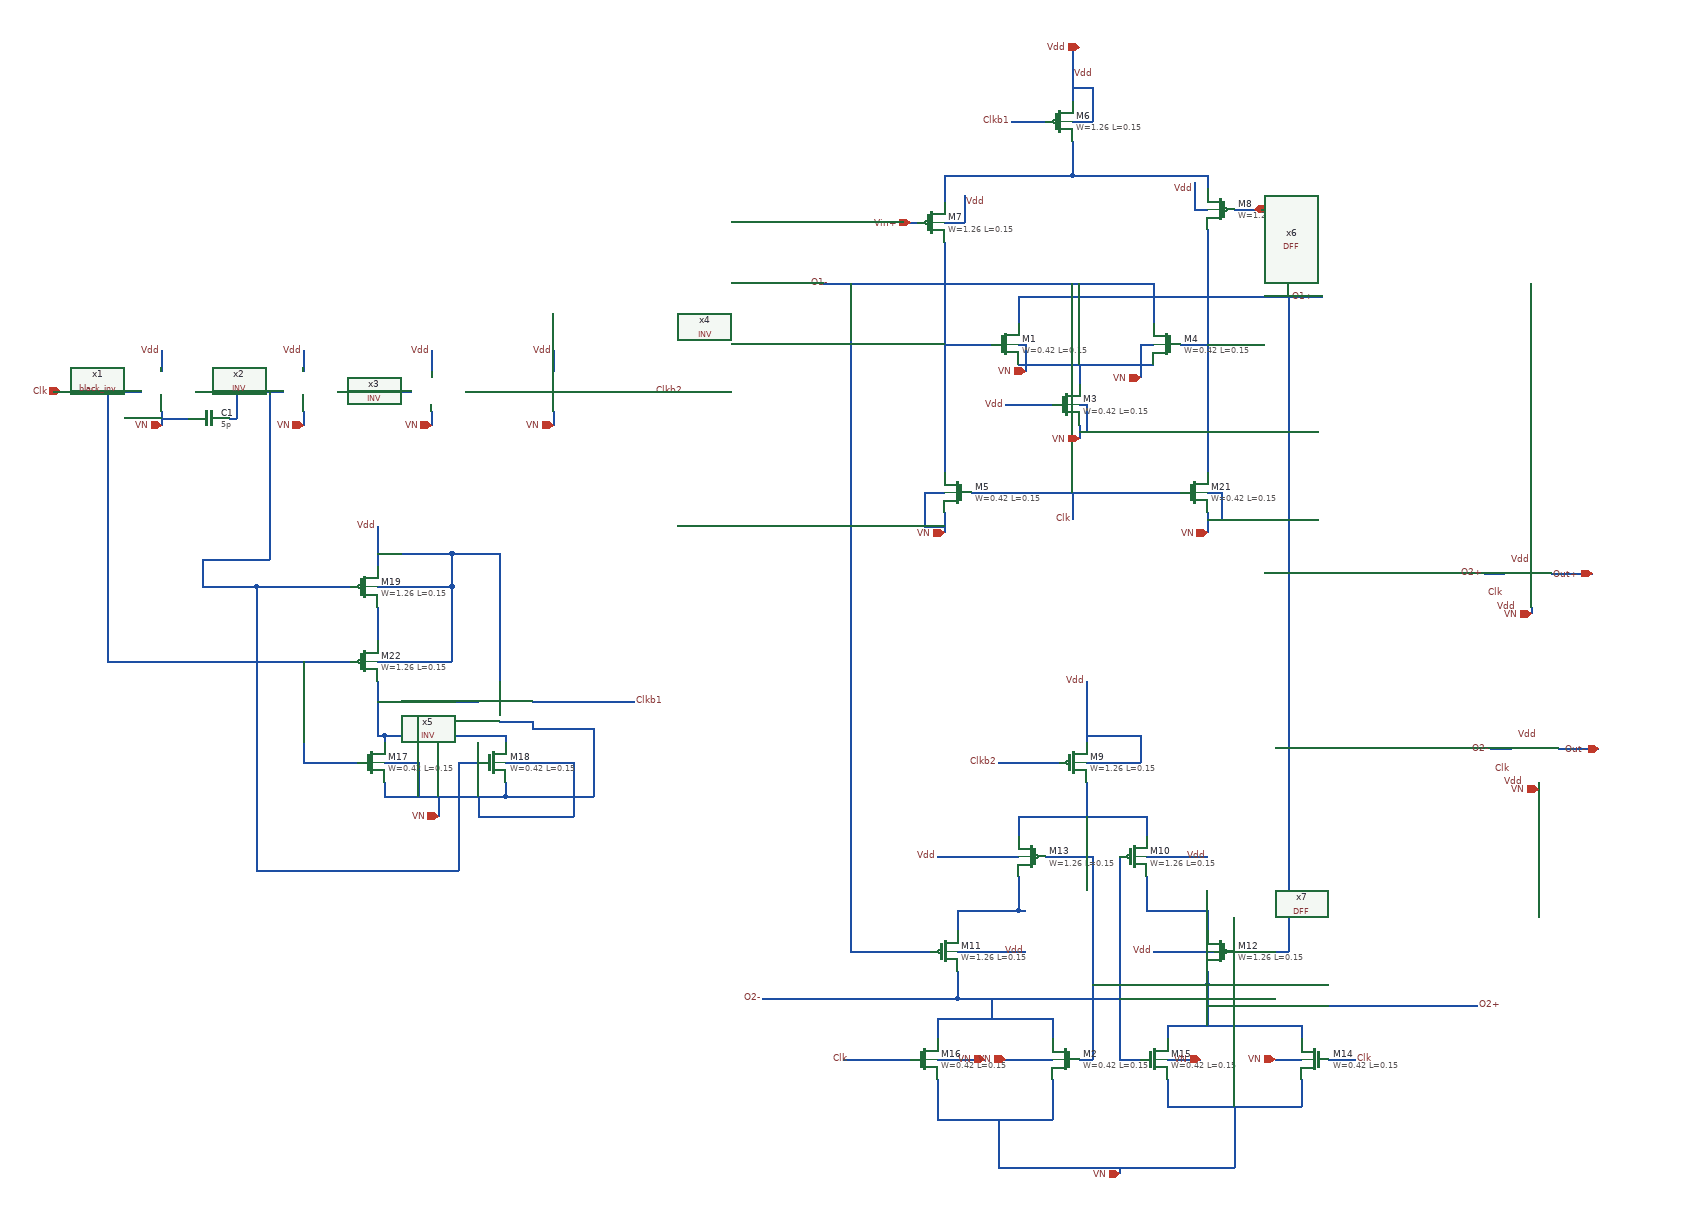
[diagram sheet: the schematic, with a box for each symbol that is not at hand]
v {xschem version=3.0.0 file_version=1.2 }
G {}
K {}
V {}
S {}
E {}
N 1790 -1710 1790 -1660 {
lab=#net1}
N 1790 -1660 1990 -1660 {
lab=#net1}
N 1990 -1660 1990 -1640 {
lab=#net1}
N 1600 -1660 1790 -1660 {
lab=#net1}
N 1600 -1660 1600 -1620 {
lab=#net1}
N 1990 -1580 1990 -1220 {
lab=O1+}
N 1600 -1560 1600 -1220 {
lab=O1-}
N 1640 -1190 1950 -1190 {
lab=Clk}
N 1710 -1380 1910 -1380 {
lab=#net2}
N 1800 -1380 1800 -1350 {
lab=#net2}
N 1690 -1320 1760 -1320 {
lab=Vdd}
N 1710 -1480 1710 -1440 {
lab=O1+}
N 1710 -1480 1990 -1480 {
lab=O1+}
N 1910 -1500 1910 -1440 {
lab=O1-}
N 1600 -1500 1910 -1500 {
lab=O1-}
N 1600 -1410 1670 -1410 {
lab=O1-}
N 1950 -1410 1990 -1410 {
lab=O1+}
N 1790 -1850 1790 -1770 {
lab=Vdd}
N 1700 -1740 1750 -1740 {
lab=Clkb1}
N 1600 -1160 1600 -1130 {
lab=VN}
N 1990 -1160 1990 -1130 {
lab=VN}
N 1800 -1290 1800 -1270 {
lab=VN}
N 1540 -1590 1560 -1590 {
lab=Vin+}
N 2030 -1610 2070 -1610 {
lab=Vin-}
N 1990 -1480 2160 -1480 {
lab=O1+}
N 1420 -1500 1600 -1500 {
lab=O1-}
N 1790 -1190 1790 -1150 {
lab=Clk}
N 1790 -1790 1820 -1790 {
lab=Vdd}
N 1820 -1790 1820 -1740 {
lab=Vdd}
N 1790 -1740 1820 -1740 {
lab=Vdd}
N 1630 -1630 1630 -1590 {
lab=Vdd}
N 1600 -1590 1630 -1590 {
lab=Vdd}
N 1970 -1650 1970 -1610 {
lab=Vdd}
N 1970 -1610 1990 -1610 {
lab=Vdd}
N 1710 -1410 1720 -1410 {
lab=VN}
N 1890 -1410 1910 -1410 {
lab=VN}
N 1800 -1280 1810 -1280 {
lab=VN}
N 1810 -1320 1810 -1280 {
lab=VN}
N 1800 -1320 1810 -1320 {
lab=VN}
N 1570 -1190 1600 -1190 {
lab=VN}
N 1570 -1190 1570 -1140 {
lab=VN}
N 1570 -1140 1600 -1140 {
lab=VN}
N 1990 -1190 2010 -1190 {
lab=VN}
N 2010 -1190 2010 -1150 {
lab=VN}
N 1990 -1150 2010 -1150 {
lab=VN}
N 1890 -1410 1890 -1360 {
lab=VN}
N 1810 -760 1810 -710 {
lab=#net3}
N 1710 -710 1710 -680 {
lab=#net3}
N 1900 -710 1900 -680 {
lab=#net3}
N 1710 -620 1710 -610 {
lab=#net4}
N 1710 -620 1710 -570 {
lab=#net4}
N 1620 -570 1710 -570 {
lab=#net4}
N 1620 -570 1620 -540 {
lab=#net4}
N 1990 -570 1990 -540 {
lab=#net5}
N 1900 -570 1990 -570 {
lab=#net5}
N 1900 -620 1900 -570 {
lab=#net5}
N 1860 -650 1860 -350 {
lab=O2-}
N 1860 -350 1890 -350 {
lab=O2-}
N 1800 -350 1820 -350 {
lab=O2+}
N 1820 -650 1820 -350 {
lab=O2+}
N 1750 -650 1820 -650 {
lab=O2+}
N 1990 -480 1990 -460 {
lab=O2+}
N 1820 -460 1990 -460 {
lab=O2+}
N 1620 -480 1620 -440 {
lab=O2-}
N 1620 -440 1860 -440 {
lab=O2-}
N 1760 -410 1760 -380 {
lab=O2-}
N 1590 -410 1760 -410 {
lab=O2-}
N 1590 -410 1590 -380 {
lab=O2-}
N 2130 -400 2130 -380 {
lab=O2+}
N 1930 -400 2130 -400 {
lab=O2+}
N 1930 -400 1930 -380 {
lab=O2+}
N 2130 -320 2130 -280 {
lab=VN}
N 1930 -280 2130 -280 {
lab=VN}
N 1930 -320 1930 -280 {
lab=VN}
N 1760 -320 1760 -260 {
lab=VN}
N 1590 -320 1590 -260 {
lab=VN}
N 1690 -350 1760 -350 {
lab=VN}
N 1590 -350 1660 -350 {
lab=VN}
N 2030 -280 2030 -190 {
lab=VN}
N 1680 -190 2030 -190 {
lab=VN}
N 1680 -260 1680 -190 {
lab=VN}
N 2030 -510 2110 -510 {
lab=O1+}
N 1540 -510 1580 -510 {
lab=O1-}
N 2170 -350 2210 -350 {
lab=Clk}
N 1450 -350 1550 -350 {
lab=Clk}
N 1900 -650 1990 -650 {
lab=Vdd}
N 1590 -650 1710 -650 {
lab=Vdd}
N 1990 -460 1990 -400 {
lab=O2+}
N 1670 -440 1670 -410 {
lab=O2-}
N 1620 -510 1720 -510 {
lab=Vdd}
N 1710 -570 1720 -570 {
lab=#net4}
N 1910 -510 2000 -510 {
lab=Vdd}
N 1930 -350 1980 -350 {
lab=VN}
N 2090 -350 2130 -350 {
lab=GND}
N 1810 -790 1890 -790 {
lab=Vdd}
N 1890 -830 1890 -790 {
lab=Vdd}
N 1870 -830 1890 -830 {
lab=Vdd}
N 1810 -830 1870 -830 {
lab=Vdd}
N 1810 -830 1810 -820 {
lab=Vdd}
N 1810 -910 1810 -820 {
lab=Vdd}
N 1690 -790 1770 -790 {
lab=Clkb2}
N 1680 -790 1690 -790 {
lab=Clkb2}
N 1330 -440 1620 -440 {
lab=O2-}
N 1990 -430 2230 -430 {
lab=O2+}
N 1710 -710 1900 -710 {
lab=#net3}
N 1460 -1500 1460 -510 {
lab=O1-}
N 1460 -510 1540 -510 {
lab=O1-}
N 2110 -1480 2110 -740 {
lab=O1+}
N 2110 -740 2110 -510 {
lab=O1+}
N 1590 -260 1760 -260 {
lab=VN}
N 700 -1340 810 -1340 {
lab=#net6}
N 890 -1340 990 -1340 {
lab=#net7}
N 440 -1400 440 -1370 {
lab=Vdd}
N 650 -1400 650 -1370 {
lab=Vdd}
N 840 -1400 840 -1370 {
lab=Vdd}
N 1020 -1400 1020 -1370 {
lab=Vdd}
N 280 -1340 410 -1340 {
lab=Clk}
N 360 -1340 360 -1140 {
lab=Clk}
N 1070 -1340 1170 -1340 {
lab=Clkb2}
N 440 -1310 440 -1290 {
lab=VN}
N 650 -1310 650 -1290 {
lab=VN}
N 840 -1310 840 -1290 {
lab=VN}
N 1020 -1310 1020 -1290 {
lab=VN}
N 360 -1140 360 -1110 {
lab=Clk}
N 760 -910 760 -830 {
lab=#net8}
N 760 -830 770 -830 {
lab=#net8}
N 770 -830 770 -820 {
lab=#net8}
N 770 -830 950 -830 {
lab=#net8}
N 950 -830 950 -820 {
lab=#net8}
N 760 -1020 760 -970 {
lab=#net9}
N 760 -1140 760 -1080 {
lab=Vdd}
N 770 -760 770 -740 {
lab=VN}
N 770 -740 950 -740 {
lab=VN}
N 950 -760 950 -740 {
lab=VN}
N 850 -740 850 -720 {
lab=VN}
N 630 -1050 720 -1050 {
lab=inv}
N 630 -940 720 -940 {
lab=Clk}
N 650 -790 730 -790 {
lab=Clk}
N 650 -940 650 -790 {
lab=Clk}
N 880 -790 910 -790 {
lab=inv}
N 880 -790 880 -710 {
lab=inv}
N 880 -710 880 -630 {
lab=inv}
N 580 -630 880 -630 {
lab=inv}
N 580 -1040 580 -630 {
lab=inv}
N 580 -1050 580 -1040 {
lab=inv}
N 580 -1050 630 -1050 {
lab=inv}
N 760 -1050 870 -1050 {
lab=Vdd}
N 760 -940 870 -940 {
lab=Vdd}
N 770 -790 820 -790 {
lab=VN}
N 950 -790 1050 -790 {
lab=VN}
N 820 -790 820 -740 {
lab=VN}
N 1050 -790 1050 -710 {
lab=VN}
N 910 -710 1050 -710 {
lab=VN}
N 910 -740 910 -710 {
lab=VN}
N 870 -1050 870 -940 {
lab=Vdd}
N 870 -1100 870 -1050 {
lab=Vdd}
N 760 -1100 870 -1100 {
lab=Vdd}
N 760 -880 910 -880 {
lab=#net8}
N 990 -880 1140 -880 {
lab=Clkb1}
N 940 -850 990 -850 {
lab=VN}
N 990 -850 990 -840 {
lab=VN}
N 870 -1100 940 -1100 {
lab=Vdd}
N 940 -1100 940 -940 {
lab=Vdd}
N 940 -940 940 -910 {
lab=Vdd}
N 950 -740 1080 -740 {
lab=VN}
N 1080 -840 1080 -740 {
lab=VN}
N 990 -840 1080 -840 {
lab=VN}
N 850 -720 850 -710 {
lab=VN}
N 360 -1110 360 -940 {
lab=Clk}
N 360 -940 630 -940 {
lab=Clk}
N 500 -1090 550 -1090 {
lab=inv}
N 500 -1090 500 -1050 {
lab=inv}
N 500 -1050 520 -1050 {
lab=inv}
N 520 -1050 580 -1050 {
lab=inv}
N 490 -1340 530 -1340 {
lab=inv}
N 590 -1340 620 -1340 {
lab=inv}
N 550 -1090 600 -1090 {
lab=inv}
N 600 -1340 600 -1090 {
lab=inv}
N 530 -1340 590 -1340 {
lab=inv}
N 440 -1300 480 -1300 {
lab=VN}
N 540 -1300 550 -1300 {
lab=inv}
N 550 -1340 550 -1300 {
lab=inv}
N 590 -1360 590 -1340 {
lab=inv}
N 2400 -1070 2430 -1070 {
lab=O2+}
N 2500 -1070 2560 -1070 {
lab=Out+}
N 2410 -810 2440 -810 {
lab=O2-}
N 2510 -810 2570 -810 {
lab=Out-}
N 2230 -430 2390 -430 {
lab=O2+}
N 2480 -760 2480 -750 {
lab=VN}
N 2470 -1020 2470 -1010 {
lab=VN}
N 1860 -190 1860 -180 {
lab=VN}
N 1720 -1410 1720 -1370 {
lab=VN}
C {devices/iopin.sym} 1550 -1590 0 0 {name=p2 lab=Vin+}
C {devices/iopin.sym} 2060 -1610 0 1 {name=p3 lab=Vin-}
C {devices/lab_pin.sym} 1690 -1320 0 0 {name=l5 sig_type=std_logic lab=Vdd}
C {devices/lab_pin.sym} 1970 -1640 0 0 {name=l18 sig_type=std_logic lab=Vdd}
C {devices/lab_pin.sym} 1630 -1620 2 0 {name=l19 sig_type=std_logic lab=Vdd}
C {devices/lab_pin.sym} 1810 -910 0 0 {name=l22 sig_type=std_logic lab=Vdd
}
C {devices/lab_pin.sym} 1590 -650 1 0 {name=l24 sig_type=std_logic lab=Vdd
}
C {devices/lab_pin.sym} 1990 -650 1 0 {name=l25 sig_type=std_logic lab=Vdd
}
C {devices/lab_pin.sym} 1720 -510 1 0 {name=l26 sig_type=std_logic lab=Vdd
}
C {devices/lab_pin.sym} 1910 -510 1 0 {name=l27 sig_type=std_logic lab=Vdd
}
C {sky130_fd_pr/pfet_01v8.sym} 1770 -1740 0 0 {name=M6
L=0.15
W=1.26
nf=1
mult=1
ad="'int((nf+1)/2) * W/nf * 0.29'" 
pd="'2*int((nf+1)/2) * (W/nf + 0.29)'"
as="'int((nf+2)/2) * W/nf * 0.29'" 
ps="'2*int((nf+2)/2) * (W/nf + 0.29)'"
nrd="'0.29 / W'" nrs="'0.29 / W'"
sa=0 sb=0 sd=0
model=pfet_01v8
spiceprefix=X
}
C {sky130_fd_pr/pfet_01v8.sym} 1580 -1590 0 0 {name=M7
L=0.15
W=1.26
nf=1
mult=1
ad="'int((nf+1)/2) * W/nf * 0.29'" 
pd="'2*int((nf+1)/2) * (W/nf + 0.29)'"
as="'int((nf+2)/2) * W/nf * 0.29'" 
ps="'2*int((nf+2)/2) * (W/nf + 0.29)'"
nrd="'0.29 / W'" nrs="'0.29 / W'"
sa=0 sb=0 sd=0
model=pfet_01v8
spiceprefix=X
}
C {sky130_fd_pr/pfet_01v8.sym} 2010 -1610 0 1 {name=M8
L=0.15
W=1.26
nf=1
mult=1
ad="'int((nf+1)/2) * W/nf * 0.29'" 
pd="'2*int((nf+1)/2) * (W/nf + 0.29)'"
as="'int((nf+2)/2) * W/nf * 0.29'" 
ps="'2*int((nf+2)/2) * (W/nf + 0.29)'"
nrd="'0.29 / W'" nrs="'0.29 / W'"
sa=0 sb=0 sd=0
model=pfet_01v8
spiceprefix=X
}
C {sky130_fd_pr/pfet_01v8.sym} 1790 -790 0 0 {name=M9
L=0.15
W=1.26
nf=1
mult=1
ad="'int((nf+1)/2) * W/nf * 0.29'" 
pd="'2*int((nf+1)/2) * (W/nf + 0.29)'"
as="'int((nf+2)/2) * W/nf * 0.29'" 
ps="'2*int((nf+2)/2) * (W/nf + 0.29)'"
nrd="'0.29 / W'" nrs="'0.29 / W'"
sa=0 sb=0 sd=0
model=pfet_01v8
spiceprefix=X
}
C {sky130_fd_pr/pfet_01v8.sym} 1880 -650 0 0 {name=M10
L=0.15
W=1.26
nf=1
mult=1
ad="'int((nf+1)/2) * W/nf * 0.29'" 
pd="'2*int((nf+1)/2) * (W/nf + 0.29)'"
as="'int((nf+2)/2) * W/nf * 0.29'" 
ps="'2*int((nf+2)/2) * (W/nf + 0.29)'"
nrd="'0.29 / W'" nrs="'0.29 / W'"
sa=0 sb=0 sd=0
model=pfet_01v8
spiceprefix=X
}
C {sky130_fd_pr/pfet_01v8.sym} 1600 -510 0 0 {name=M11
L=0.15
W=1.26
nf=1
mult=1
ad="'int((nf+1)/2) * W/nf * 0.29'" 
pd="'2*int((nf+1)/2) * (W/nf + 0.29)'"
as="'int((nf+2)/2) * W/nf * 0.29'" 
ps="'2*int((nf+2)/2) * (W/nf + 0.29)'"
nrd="'0.29 / W'" nrs="'0.29 / W'"
sa=0 sb=0 sd=0
model=pfet_01v8
spiceprefix=X
}
C {sky130_fd_pr/pfet_01v8.sym} 2010 -510 0 1 {name=M12
L=0.15
W=1.26
nf=1
mult=1
ad="'int((nf+1)/2) * W/nf * 0.29'" 
pd="'2*int((nf+1)/2) * (W/nf + 0.29)'"
as="'int((nf+2)/2) * W/nf * 0.29'" 
ps="'2*int((nf+2)/2) * (W/nf + 0.29)'"
nrd="'0.29 / W'" nrs="'0.29 / W'"
sa=0 sb=0 sd=0
model=pfet_01v8
spiceprefix=X
}
C {sky130_fd_pr/pfet_01v8.sym} 1730 -650 0 1 {name=M13
L=0.15
W=1.26
nf=1
mult=1
ad="'int((nf+1)/2) * W/nf * 0.29'" 
pd="'2*int((nf+1)/2) * (W/nf + 0.29)'"
as="'int((nf+2)/2) * W/nf * 0.29'" 
ps="'2*int((nf+2)/2) * (W/nf + 0.29)'"
nrd="'0.29 / W'" nrs="'0.29 / W'"
sa=0 sb=0 sd=0
model=pfet_01v8
spiceprefix=X
}
C {sky130_fd_pr/nfet_01v8.sym} 1690 -1410 0 0 {name=M1
L=0.15
W=0.42
nf=1 
mult=1
ad="'int((nf+1)/2) * W/nf * 0.29'" 
pd="'2*int((nf+1)/2) * (W/nf + 0.29)'"
as="'int((nf+2)/2) * W/nf * 0.29'" 
ps="'2*int((nf+2)/2) * (W/nf + 0.29)'"
nrd="'0.29 / W'" nrs="'0.29 / W'"
sa=0 sb=0 sd=0
model=nfet_01v8
spiceprefix=X
}
C {sky130_fd_pr/nfet_01v8.sym} 1780 -1320 0 0 {name=M3
L=0.15
W=0.42
nf=1 
mult=1
ad="'int((nf+1)/2) * W/nf * 0.29'" 
pd="'2*int((nf+1)/2) * (W/nf + 0.29)'"
as="'int((nf+2)/2) * W/nf * 0.29'" 
ps="'2*int((nf+2)/2) * (W/nf + 0.29)'"
nrd="'0.29 / W'" nrs="'0.29 / W'"
sa=0 sb=0 sd=0
model=nfet_01v8
spiceprefix=X
}
C {sky130_fd_pr/nfet_01v8.sym} 1930 -1410 0 1 {name=M4
L=0.15
W=0.42
nf=1 
mult=1
ad="'int((nf+1)/2) * W/nf * 0.29'" 
pd="'2*int((nf+1)/2) * (W/nf + 0.29)'"
as="'int((nf+2)/2) * W/nf * 0.29'" 
ps="'2*int((nf+2)/2) * (W/nf + 0.29)'"
nrd="'0.29 / W'" nrs="'0.29 / W'"
sa=0 sb=0 sd=0
model=nfet_01v8
spiceprefix=X
}
C {sky130_fd_pr/nfet_01v8.sym} 1620 -1190 0 1 {name=M5
L=0.15
W=0.42
nf=1 
mult=1
ad="'int((nf+1)/2) * W/nf * 0.29'" 
pd="'2*int((nf+1)/2) * (W/nf + 0.29)'"
as="'int((nf+2)/2) * W/nf * 0.29'" 
ps="'2*int((nf+2)/2) * (W/nf + 0.29)'"
nrd="'0.29 / W'" nrs="'0.29 / W'"
sa=0 sb=0 sd=0
model=nfet_01v8
spiceprefix=X
}
C {sky130_fd_pr/nfet_01v8.sym} 1970 -1190 0 0 {name=M21
L=0.15
W=0.42
nf=1 
mult=1
ad="'int((nf+1)/2) * W/nf * 0.29'" 
pd="'2*int((nf+1)/2) * (W/nf + 0.29)'"
as="'int((nf+2)/2) * W/nf * 0.29'" 
ps="'2*int((nf+2)/2) * (W/nf + 0.29)'"
nrd="'0.29 / W'" nrs="'0.29 / W'"
sa=0 sb=0 sd=0
model=nfet_01v8
spiceprefix=X
}
C {sky130_fd_pr/nfet_01v8.sym} 1780 -350 0 1 {name=M2
L=0.15
W=0.42
nf=1 
mult=1
ad="'int((nf+1)/2) * W/nf * 0.29'" 
pd="'2*int((nf+1)/2) * (W/nf + 0.29)'"
as="'int((nf+2)/2) * W/nf * 0.29'" 
ps="'2*int((nf+2)/2) * (W/nf + 0.29)'"
nrd="'0.29 / W'" nrs="'0.29 / W'"
sa=0 sb=0 sd=0
model=nfet_01v8
spiceprefix=X
}
C {sky130_fd_pr/nfet_01v8.sym} 2150 -350 0 1 {name=M14
L=0.15
W=0.42
nf=1 
mult=1
ad="'int((nf+1)/2) * W/nf * 0.29'" 
pd="'2*int((nf+1)/2) * (W/nf + 0.29)'"
as="'int((nf+2)/2) * W/nf * 0.29'" 
ps="'2*int((nf+2)/2) * (W/nf + 0.29)'"
nrd="'0.29 / W'" nrs="'0.29 / W'"
sa=0 sb=0 sd=0
model=nfet_01v8
spiceprefix=X
}
C {sky130_fd_pr/nfet_01v8.sym} 1910 -350 0 0 {name=M15
L=0.15
W=0.42
nf=1 
mult=1
ad="'int((nf+1)/2) * W/nf * 0.29'" 
pd="'2*int((nf+1)/2) * (W/nf + 0.29)'"
as="'int((nf+2)/2) * W/nf * 0.29'" 
ps="'2*int((nf+2)/2) * (W/nf + 0.29)'"
nrd="'0.29 / W'" nrs="'0.29 / W'"
sa=0 sb=0 sd=0
model=nfet_01v8
spiceprefix=X
}
C {sky130_fd_pr/nfet_01v8.sym} 1570 -350 0 0 {name=M16
L=0.15
W=0.42
nf=1 
mult=1
ad="'int((nf+1)/2) * W/nf * 0.29'" 
pd="'2*int((nf+1)/2) * (W/nf + 0.29)'"
as="'int((nf+2)/2) * W/nf * 0.29'" 
ps="'2*int((nf+2)/2) * (W/nf + 0.29)'"
nrd="'0.29 / W'" nrs="'0.29 / W'"
sa=0 sb=0 sd=0
model=nfet_01v8
spiceprefix=X
}
C {devices/lab_pin.sym} 1680 -790 0 0 {name=l51 sig_type=std_logic lab=Clkb2}
C {devices/lab_pin.sym} 2210 -350 2 0 {name=l54 sig_type=std_logic lab=Clk}
C {devices/lab_pin.sym} 1460 -350 0 0 {name=l55 sig_type=std_logic lab=Clk}
C {devices/ipin.sym} 1800 -1850 0 0 {name=p5 lab=Vdd}
C {devices/lab_pin.sym} 1790 -1810 2 0 {name=l4 sig_type=std_logic lab=Vdd}
C {devices/lab_pin.sym} 2150 -1480 1 0 {name=l56 sig_type=std_logic lab=O1+}
C {devices/lab_pin.sym} 1430 -1500 1 0 {name=l57 sig_type=std_logic lab=O1-}
C {devices/lab_pin.sym} 1700 -1740 0 0 {name=l7 sig_type=std_logic lab=Clkb1}
C {devices/lab_pin.sym} 1790 -1150 3 0 {name=l10 sig_type=std_logic lab=Clk}
C {devices/lab_pin.sym} 440 -1400 1 0 {name=l20 sig_type=std_logic lab=Vdd}
C {devices/lab_pin.sym} 650 -1400 1 0 {name=l21 sig_type=std_logic lab=Vdd}
C {devices/lab_pin.sym} 840 -1400 1 0 {name=l31 sig_type=std_logic lab=Vdd}
C {devices/lab_pin.sym} 1020 -1400 1 0 {name=l34 sig_type=std_logic lab=Vdd}
C {devices/lab_pin.sym} 760 -1140 1 0 {name=l8 sig_type=std_logic lab=Vdd}
C {sky130_fd_pr/nfet_01v8.sym} 750 -790 0 0 {name=M17
L=0.15
W=0.42
nf=1 
mult=1
ad="'int((nf+1)/2) * W/nf * 0.29'" 
pd="'2*int((nf+1)/2) * (W/nf + 0.29)'"
as="'int((nf+2)/2) * W/nf * 0.29'" 
ps="'2*int((nf+2)/2) * (W/nf + 0.29)'"
nrd="'0.29 / W'" nrs="'0.29 / W'"
sa=0 sb=0 sd=0
model=nfet_01v8
spiceprefix=X
}
C {sky130_fd_pr/nfet_01v8.sym} 930 -790 0 0 {name=M18
L=0.15
W=0.42
nf=1 
mult=1
ad="'int((nf+1)/2) * W/nf * 0.29'" 
pd="'2*int((nf+1)/2) * (W/nf + 0.29)'"
as="'int((nf+2)/2) * W/nf * 0.29'" 
ps="'2*int((nf+2)/2) * (W/nf + 0.29)'"
nrd="'0.29 / W'" nrs="'0.29 / W'"
sa=0 sb=0 sd=0
model=nfet_01v8
spiceprefix=X
}
C {sky130_fd_pr/pfet_01v8.sym} 740 -1050 0 0 {name=M19
L=0.15
W=1.26
nf=1
mult=1
ad="'int((nf+1)/2) * W/nf * 0.29'" 
pd="'2*int((nf+1)/2) * (W/nf + 0.29)'"
as="'int((nf+2)/2) * W/nf * 0.29'" 
ps="'2*int((nf+2)/2) * (W/nf + 0.29)'"
nrd="'0.29 / W'" nrs="'0.29 / W'"
sa=0 sb=0 sd=0
model=pfet_01v8
spiceprefix=X
}
C {sky130_fd_pr/pfet_01v8.sym} 740 -940 0 0 {name=M22
L=0.15
W=1.26
nf=1
mult=1
ad="'int((nf+1)/2) * W/nf * 0.29'" 
pd="'2*int((nf+1)/2) * (W/nf + 0.29)'"
as="'int((nf+2)/2) * W/nf * 0.29'" 
ps="'2*int((nf+2)/2) * (W/nf + 0.29)'"
nrd="'0.29 / W'" nrs="'0.29 / W'"
sa=0 sb=0 sd=0
model=pfet_01v8
spiceprefix=X
}
C {devices/lab_pin.sym} 1170 -1340 2 0 {name=l52 sig_type=std_logic lab=Clkb2}
C {devices/ipin.sym} 290 -1340 0 0 {name=p6 lab=Clk}
C {devices/lab_pin.sym} 330 -1340 1 0 {name=l58 sig_type=std_logic lab=Clk}
C {devices/lab_pin.sym} 1140 -880 2 0 {name=l6 sig_type=std_logic lab=Clkb1}
C {devices/capa.sym} 510 -1300 1 0 {name=C1
m=1
value=5p
footprint=1206
device="ceramic capacitor"}
C {devices/lab_pin.sym} 590 -1360 1 0 {name=l11 sig_type=std_logic lab=inv}
C {pico_chipathon/component/black_inv_1/black_inv.sym} 320 -1340 0 0 {name=x1}
C {pico_chipathon/component/INV/INV.sym} 600 -1340 0 0 {name=x2}
C {pico_chipathon/component/INV/INV.sym} 790 -1340 0 0 {name=x3}
C {pico_chipathon/component/INV/INV.sym} 970 -1340 0 0 {name=x4}
C {pico_chipathon/component/INV/INV.sym} 890 -880 0 0 {name=x5}
C {pico_chipathon/component/FlipFlops/DFF.sym} 2390 -1010 0 0 {name=x6}
C {devices/lab_pin.sym} 2430 -1040 0 0 {name=l33 sig_type=std_logic lab=Clk}
C {devices/iopin.sym} 2560 -1070 0 0 {name=p1 lab=Out+}
C {devices/lab_pin.sym} 2470 -1090 1 0 {name=l35 sig_type=std_logic lab=Vdd
}
C {devices/lab_pin.sym} 2450 -1020 3 0 {name=l40 sig_type=std_logic lab=Vdd
}
C {pico_chipathon/component/FlipFlops/DFF.sym} 2400 -750 0 0 {name=x7}
C {devices/lab_pin.sym} 2440 -780 0 0 {name=l12 sig_type=std_logic lab=Clk}
C {devices/iopin.sym} 2570 -810 0 0 {name=p7 lab=Out-}
C {devices/lab_pin.sym} 2480 -830 1 0 {name=l13 sig_type=std_logic lab=Vdd
}
C {devices/lab_pin.sym} 2460 -760 3 0 {name=l14 sig_type=std_logic lab=Vdd
}
C {devices/lab_pin.sym} 1330 -440 0 0 {name=l42 sig_type=std_logic lab=O2-}
C {devices/lab_pin.sym} 2390 -430 2 0 {name=l43 sig_type=std_logic lab=O2+}
C {devices/lab_pin.sym} 2400 -1070 0 0 {name=l44 sig_type=std_logic lab=O2+}
C {devices/lab_pin.sym} 2410 -810 0 0 {name=l45 sig_type=std_logic lab=O2-}
C {devices/ipin.sym} 440 -1290 3 0 {name=p4 lab=VN}
C {devices/ipin.sym} 650 -1290 3 0 {name=p8 lab=VN}
C {devices/ipin.sym} 840 -1290 3 0 {name=p9 lab=VN}
C {devices/ipin.sym} 1020 -1290 3 0 {name=p10 lab=VN}
C {devices/ipin.sym} 850 -710 3 0 {name=p11 lab=VN}
C {devices/ipin.sym} 1800 -1270 3 0 {name=p12 lab=VN}
C {devices/ipin.sym} 1600 -1130 3 0 {name=p13 lab=VN}
C {devices/ipin.sym} 1990 -1130 3 0 {name=p14 lab=VN}
C {devices/ipin.sym} 1860 -180 3 0 {name=p15 lab=VN}
C {devices/ipin.sym} 2480 -750 3 0 {name=p16 lab=VN}
C {devices/ipin.sym} 2470 -1010 3 0 {name=p17 lab=VN}
C {devices/ipin.sym} 1660 -350 3 0 {name=p18 lab=VN}
C {devices/ipin.sym} 1690 -350 3 0 {name=p19 lab=VN}
C {devices/ipin.sym} 1980 -350 3 0 {name=p20 lab=VN}
C {devices/ipin.sym} 1720 -1370 3 0 {name=p21 lab=VN}
C {devices/ipin.sym} 1890 -1360 3 0 {name=p22 lab=VN}
C {devices/ipin.sym} 2090 -350 3 0 {name=p23 lab=VN}
